! (c) 2009  Infineon Technologies AG, Munich
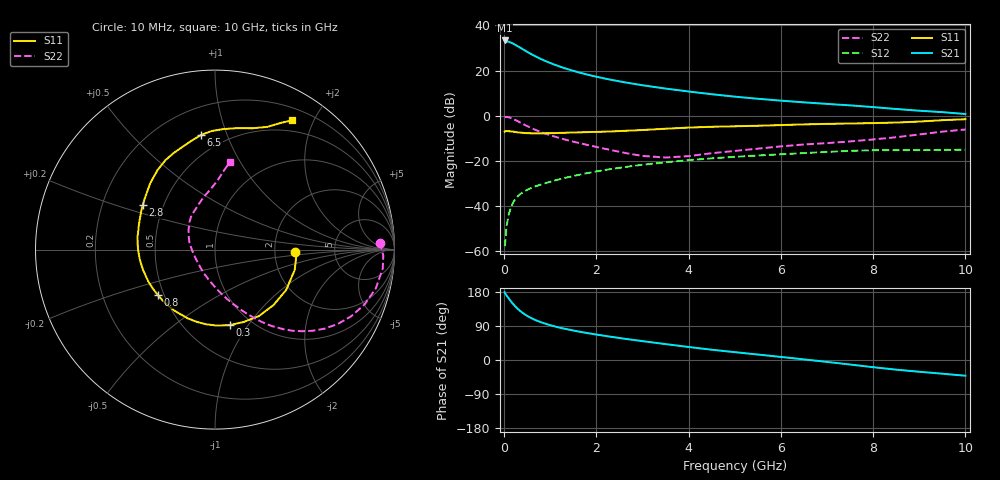
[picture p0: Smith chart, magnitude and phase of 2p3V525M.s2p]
! Infineon Technologies  Discrete & RF Semiconductors
! BFP420
! VCE =  3.5 V,  IC =  25 mA
! Common Emitter S-Parameters:  Nov 2009
# GHz  S  MA  R  50
!  f  S11  S21  S12  S22
! GHz  MAG  ANG  MAG  ANG  MAG  ANG  MAG  ANG
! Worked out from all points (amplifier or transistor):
!   46 points, 10 MHz to 10 GHz, reference 50 ohm
!   highest |S21| = 33.3 dB at 10 MHz (marker M1)
!   |S21| within 3 dB of that: start of sweep to 331.8 MHz
!   unconditionally stable (mu >= 1): start of sweep to 14.32 MHz; 1.692 GHz to end of sweep
!   at 300 MHz: K = 0.37, MSG = 33.2 dB, |S12| = -35.6 dB
!   at 1.7 GHz: K = 1.00, MAG = 22.0 dB, |S12| = -25.8 dB
!   at 10 GHz: K = 1.06, MAG = 6.3 dB, |S12| = -15.0 dB
!   lowest NFmin = 1.38 dB at 900 MHz
!   S11 on the Smith chart (normalised r, x): 10 MHz: 2.61, -0.10; 300 MHz: 0.80, -0.83; 800 MHz: 0.46, -0.28; 2.8 GHz: 0.38, +0.25; 6.5 GHz: 0.37, +0.82; 10 GHz: 0.35, +1.71
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0.01  0.4462 -2.0  46.35 178.8  0.0013 86.9  0.9191 2.4
0.02  0.4541 -5.4  45.05 175.9  0.0014 74.1  0.9382 -2.0
0.1  0.4559 -29.7  43.37 162.3  0.0066 76.9  0.9217 -13.6
0.15  0.449 -43.5  41.43 154.3  0.0096 73.3  0.8872 -20.2
0.2  0.4439 -56.4  39.19 147.0  0.0123 69.7  0.8447 -26.1
0.25  0.434 -68.2  36.64 140.3  0.0146 67.0  0.7989 -31.3
0.3  0.4285 -78.9  34.31 134.4  0.0166 64.5  0.7518 -35.9
0.4  0.4192 -96.9  29.8 124.4  0.0201 60.8  0.6643 -43.2
0.5  0.412 -111.6  25.92 116.4  0.023 58.6  0.5895 -49.0
0.6  0.4087 -123.4  22.74 109.8  0.0255 57.2  0.5279 -53.6
0.8  0.407 -141.4  17.96 99.6  0.0301 56.2  0.4356 -60.5
1  0.4117 -154.6  14.68 91.8  0.0347 55.9  0.3701 -66.2
1.2  0.4168 -164.7  12.31 85.5  0.0393 55.7  0.3213 -71.3
1.7  0.4314 176.5  8.668 73.3  0.0512 54.2  0.239 -83.5
2.2  0.4453 162.5  6.608 63.4  0.0634 51.3  0.1845 -96.9
2.8  0.4728 148.3  5.098 53.0  0.0776 46.8  0.1393 -119.3
3.5  0.5164 134.4  3.995 41.9  0.0933 40.8  0.1189 -154.5
5.5  0.6004 107.6  2.375 14.4  0.1318 22.5  0.1871 141.7
6.5  0.644 96.8  1.979 1.6  0.1493 13.4  0.2317 124.4
7  0.6609 91.6  1.829 -5.1  0.1585 8.6  0.248 116.4
8.5  0.7072 72.9  1.411 -25.5  0.1732 -8.3  0.335 94.5
10  0.8389 59.2  1.091 -41.5  0.1773 -19.6  0.4964 80.2
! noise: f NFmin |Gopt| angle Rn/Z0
0.9  1.38  0.22  -154  0.13
1.8  1.65  0.29  -143  0.13
2.4  1.81  0.26  -138  0.17
3  1.83  0.34  -129  0.18
4  1.97  0.45  -112  0.27
5  2.4  0.49  -95  0.44
6  2.85  0.54  -84  0.65
